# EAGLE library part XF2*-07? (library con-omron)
OMRON FPC Connector Source : http://www.omron.com/ecb/products/pdf/fpc.pdf

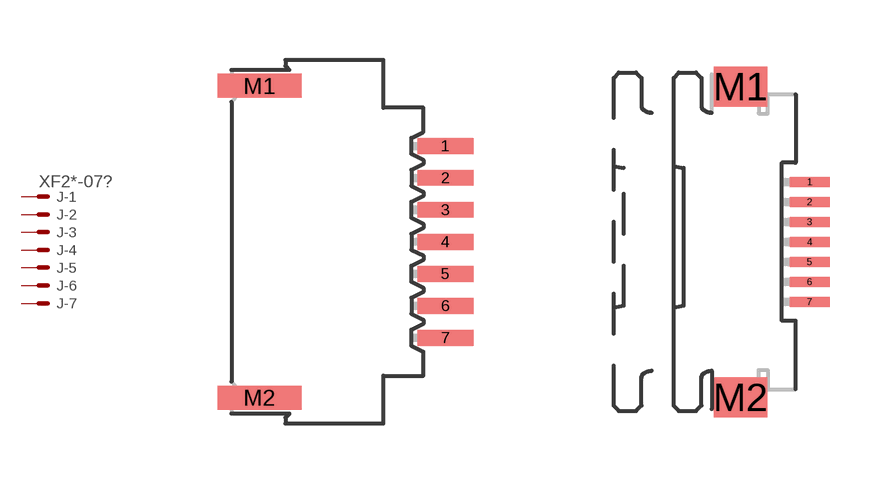
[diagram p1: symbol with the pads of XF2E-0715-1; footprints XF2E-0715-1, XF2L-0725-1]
Designator prefix J; gates -1=PV -2=P -3=P -4=P -5=P -6=P -7=P

## XF2E-0715-1 (OC_FARNELL: unknown; OC_NEWARK: unknown)  [XF2E-0715-1]
1  -1:MSV  pas
2  -2:MS  pas
3  -3:MS  pas
4  -4:MS  pas
5  -5:MS  pas
6  -6:MS  pas
7  -7:MS  pas

## XF2L-0725-1 (MPN: XF2L-0725-1; OC_FARNELL: unknown; OC_NEWARK: 37M0868)  [XF2L-0725-1]
Pads as for XF2E-0715-1

## XF2L-0735-1 (MPN: XF2L-0735-1; OC_FARNELL: unknown; OC_NEWARK: 37M0870)  [XF2L-0735-1]
Pads as for XF2E-0715-1

## Footprint XF2E-0715-1 (pad centres in mm)
Non-ZIF Type (0.8 mm-pitch) Source : http://www.omron.com/ecb/products/pdf/fpc.pdf
smd 1.4 x 0.4: 1 2.54,2.4; 2 2.54,1.6; 3 2.54,0.8; 4 2.54,0; 5 2.54,-0.8; 6 2.54,-1.6; 7 2.54,-2.4
smd 2.1 x 0.6: M1 -2.11,3.9; M2 -2.11,-3.9

## Footprint XF2L-0725-1 (pad centres in mm)
ZIF Slide-locking Type (0.5 mm-pitch) Upper-contact Type Source : http://www.omron.com/ecb/products/pdf/fpc.pdf
smd 1 x 0.25: 1 1.905,1.5; 2 1.905,1; 3 1.905,0.5; 4 1.905,0; 5 1.905,-0.5; 6 1.905,-1; 7 1.905,-1.5
smd 1.34 x 1: M1 0.18,3.888; M2 0.18,-3.888

## Footprint XF2L-0735-1 (pad centres in mm)
ZIF Slide-locking Type (0.5 mm-pitch) Lower-contact Type Source : http://www.omron.com/ecb/products/pdf/fpc.pdf
smd 1 x 0.25: 1 1.905,1.5; 2 1.905,1; 3 1.905,0.5; 4 1.905,0; 5 1.905,-0.5; 6 1.905,-1; 7 1.905,-1.5
smd 1.34 x 1: M1 0.18,3.888; M2 0.18,-3.888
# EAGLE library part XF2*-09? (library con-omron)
OMRON FPC Connector Source : http://www.omron.com/ecb/products/pdf/fpc.pdf

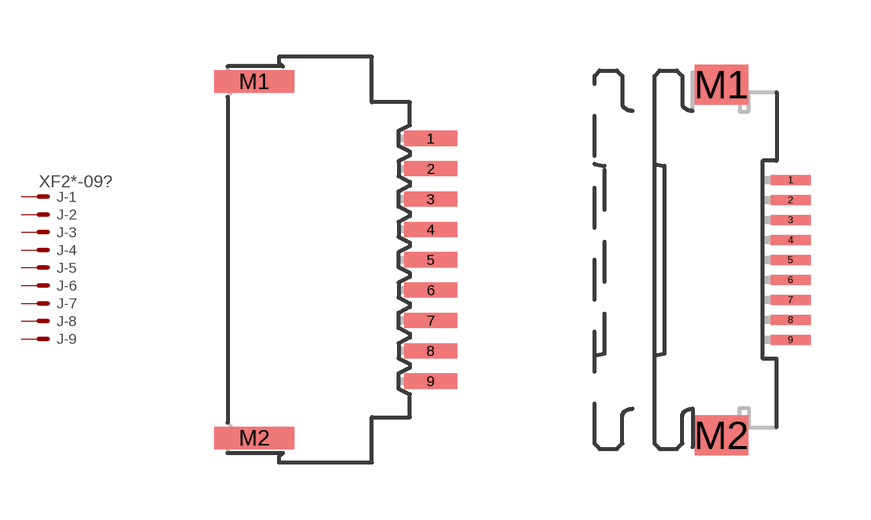
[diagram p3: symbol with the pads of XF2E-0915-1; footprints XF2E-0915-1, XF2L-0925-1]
Designator prefix J; gates -1=PV -2=P -3=P -4=P -5=P -6=P -7=P -8=P -9=P

## XF2E-0915-1 (MPN: XF2E-0915-1; OC_FARNELL: unknown; OC_NEWARK: 37M9452)  [XF2E-0915-1]
1  -1:MSV  pas
2  -2:MS  pas
3  -3:MS  pas
4  -4:MS  pas
5  -5:MS  pas
6  -6:MS  pas
7  -7:MS  pas
8  -8:MS  pas
9  -9:MS  pas

## XF2L-0925-1 (MPN: XF2L-0925-1A; OC_FARNELL: unknown; OC_NEWARK: 05M1991)  [XF2L-0925-1]
Pads as for XF2E-0915-1

## XF2R-0915-4A (MPN: XF2R-0915-4A; OC_FARNELL: unknown; OC_NEWARK: 37M0944)  [XF2R-0915-4A]
Pads as for XF2E-0915-1

## Footprint XF2E-0915-1 (pad centres in mm)
Non-ZIF Type (0.8 mm-pitch) Source : http://www.omron.com/ecb/products/pdf/fpc.pdf
smd 1.4 x 0.4: 1 2.54,3.2; 2 2.54,2.4; 3 2.54,1.6; 4 2.54,0.8; 5 2.54,0; 6 2.54,-0.8; 7 2.54,-1.6; 8 2.54,-2.4; 9 2.54,-3.2
smd 2.1 x 0.6: M1 -2.11,4.7; M2 -2.11,-4.7

## Footprint XF2L-0925-1 (pad centres in mm)
ZIF Slide-locking Type (0.5 mm-pitch) Upper-contact Type Source : http://www.omron.com/ecb/products/pdf/fpc.pdf
smd 1 x 0.25: 1 1.905,2; 2 1.905,1.5; 3 1.905,1; 4 1.905,0.5; 5 1.905,0; 6 1.905,-0.5; 7 1.905,-1; 8 1.905,-1.5; 9 1.905,-2
smd 1.34 x 1: M1 0.18,4.388; M2 0.18,-4.388

## Footprint XF2R-0915-4A (pad centres in mm)
Low-profile Rotary Backlock Type (0.5 mm-pitch) Source : http://www.omron.com/ecb/products/pdf/fpc.pdf
smd 0.85 x 0.25: 1 -2.54,2; 2 -2.54,1.5; 3 -2.54,1; 4 -2.54,0.5; 5 -2.54,0; 6 -2.54,-0.5; 7 -2.54,-1; 8 -2.54,-1.5; 9 -2.54,-2
smd 1.4 x 1: M1 -0.915,3.3; M2 -0.915,-3.3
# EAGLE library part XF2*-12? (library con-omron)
OMRON FPC Connector Source : http://www.omron.com/ecb/products/pdf/fpc.pdf

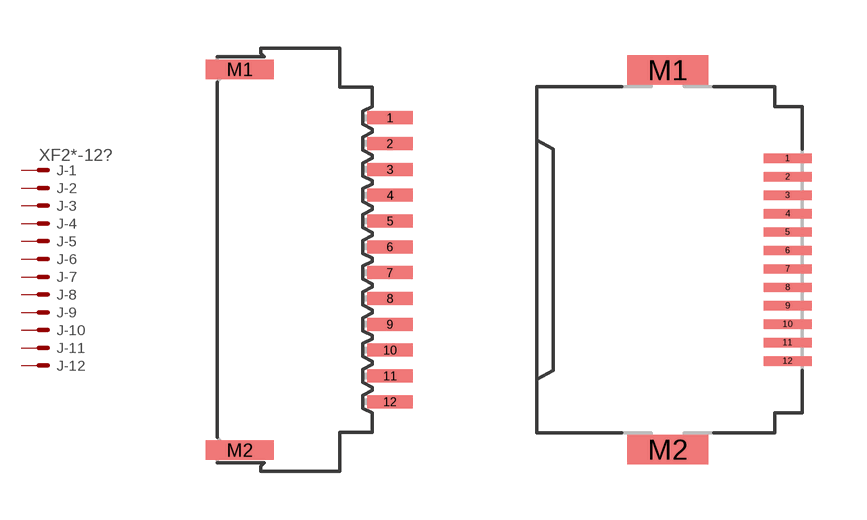
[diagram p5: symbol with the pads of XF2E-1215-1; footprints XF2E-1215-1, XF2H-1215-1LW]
Designator prefix J; gates -1=PV -2=P -3=P -4=P -5=P -6=P -7=P -8=P -9=P -10=P -11=P -12=P

## XF2E-1215-1 (OC_FARNELL: unknown; OC_NEWARK: unknown)  [XF2E-1215-1]
1  -1:MSV  pas
2  -2:MS  pas
3  -3:MS  pas
4  -4:MS  pas
5  -5:MS  pas
6  -6:MS  pas
7  -7:MS  pas
8  -8:MS  pas
9  -9:MS  pas
10  -10:MS  pas
11  -11:MS  pas
12  -12:MS  pas

## XF2H-1215-1LW (OC_FARNELL: unknown; OC_NEWARK: unknown)  [XF2H-1215-1LW]
Pads as for XF2E-1215-1

## XF2J-1224-11 (MPN: XF2J-1224-11A; OC_FARNELL: 1430936; OC_NEWARK: 37M0822)  [XF2J-1224-11]
Pads as for XF2E-1215-1

## XF2J-1224-12 (MPN: XF2J-1224-12A; OC_FARNELL: 1430940; OC_NEWARK: 59M3512)  [XF2J-1224-12]
Pads as for XF2E-1215-1

## XF2L-1225-1 (MPN: XF2L-1225-1A; OC_FARNELL: unknown; OC_NEWARK: 05M1993)  [XF2L-1225-1]
Pads as for XF2E-1215-1

## XF2L-1235-1 (MPN: XF2L-1235-1; OC_FARNELL: unknown; OC_NEWARK: 37M0880)  [XF2L-1235-1]
Pads as for XF2E-1215-1

## Footprint XF2E-1215-1 (pad centres in mm)
Non-ZIF Type (0.8 mm-pitch) Source : http://www.omron.com/ecb/products/pdf/fpc.pdf
smd 1.4 x 0.4: 1 2.54,4.4; 2 2.54,3.6; 3 2.54,2.8; 4 2.54,2; 5 2.54,1.2; 6 2.54,0.4; 7 2.54,-0.4; 8 2.54,-1.2; 9 2.54,-2; 10 2.54,-2.8; 11 2.54,-3.6; 12 2.54,-4.4
smd 2.1 x 0.6: M1 -2.11,5.9; M2 -2.11,-5.9

## Footprint XF2H-1215-1LW (pad centres in mm)
Standard Rotary Backlock Type (0.5 mm-pitch) Source : http://www.omron.com/ecb/products/pdf/fpc.pdf
smd 1.3 x 0.25: 1 3.175,2.75; 2 3.175,2.25; 3 3.175,1.75; 4 3.175,1.25; 5 3.175,0.75; 6 3.175,0.25; 7 3.175,-0.25; 8 3.175,-0.75; 9 3.175,-1.25; 10 3.175,-1.75; 11 3.175,-2.25; 12 3.175,-2.75
smd 2.2 x 0.8: M1 -0.075,5.15; M2 -0.075,-5.15

## Footprint XF2J-1224-11 (pad centres in mm)
ZIF Slide-locking Type (0.5 mm-pitch) Standard Source : http://www.omron.com/ecb/products/pdf/fpc.pdf
smd 1.6 x 0.5: 1 1.2,2.75; 2 -1.2,2.25; 3 1.2,1.75; 4 -1.2,1.25; 5 1.2,0.75; 6 -1.2,0.25; 7 1.2,-0.25; 8 -1.2,-0.75; 9 1.2,-1.25; 10 -1.2,-1.75; 11 1.2,-2.25; 12 -1.2,-2.75
smd 2.9 x 1.4: M1 0,4.45; M2 0,-4.45

## Footprint XF2J-1224-12 (pad centres in mm)
ZIF Slide-locking Type (0.5 mm-pitch) Reverse Source : http://www.omron.com/ecb/products/pdf/fpc.pdf
smd 1.6 x 0.5: 1 -1.2,2.75; 2 1.2,2.25; 3 -1.2,1.75; 4 1.2,1.25; 5 -1.2,0.75; 6 1.2,0.25; 7 -1.2,-0.25; 8 1.2,-0.75; 9 -1.2,-1.25; 10 1.2,-1.75; 11 -1.2,-2.25; 12 1.2,-2.75
smd 2.9 x 1.4: M1 0,4.45; M2 0,-4.45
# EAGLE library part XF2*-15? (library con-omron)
OMRON FPC Connector Source : http://www.omron.com/ecb/products/pdf/fpc.pdf

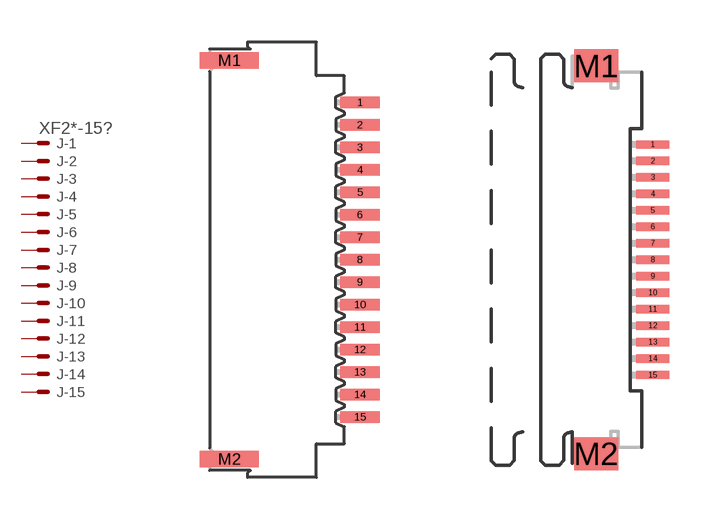
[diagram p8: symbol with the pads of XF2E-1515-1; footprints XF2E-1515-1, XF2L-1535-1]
Designator prefix J; gates -1=PV -2=P -3=P -4=P -5=P -6=P -7=P -8=P -9=P -10=P -11=P -12=P -13=P -14=P -15=P

## XF2E-1515-1 (OC_FARNELL: unknown; OC_NEWARK: unknown)  [XF2E-1515-1]
1  -1:MSV  pas
2  -2:MS  pas
3  -3:MS  pas
4  -4:MS  pas
5  -5:MS  pas
6  -6:MS  pas
7  -7:MS  pas
8  -8:MS  pas
9  -9:MS  pas
10  -10:MS  pas
11  -11:MS  pas
12  -12:MS  pas
13  -13:MS  pas
14  -14:MS  pas
15  -15:MS  pas

## XF2L-1535-1 (MPN: XF2L-1535-1A; OC_FARNELL: unknown; OC_NEWARK: 05M1997)  [XF2L-1535-1]
Pads as for XF2E-1515-1

## Footprint XF2E-1515-1 (pad centres in mm)
Non-ZIF Type (0.8 mm-pitch) Source : http://www.omron.com/ecb/products/pdf/fpc.pdf
smd 1.4 x 0.4: 1 2.54,5.6; 2 2.54,4.8; 3 2.54,4; 4 2.54,3.2; 5 2.54,2.4; 6 2.54,1.6; 7 2.54,0.8; 8 2.54,0; 9 2.54,-0.8; 10 2.54,-1.6; 11 2.54,-2.4; 12 2.54,-3.2; 13 2.54,-4; 14 2.54,-4.8; 15 2.54,-5.6
smd 2.1 x 0.6: M1 -2.11,7.1; M2 -2.11,-7.1

## Footprint XF2L-1535-1 (pad centres in mm)
ZIF Slide-locking Type (0.5 mm-pitch) Lower-contact Type Source : http://www.omron.com/ecb/products/pdf/fpc.pdf
smd 1 x 0.25: 1 1.905,3.5; 2 1.905,3; 3 1.905,2.5; 4 1.905,2; 5 1.905,1.5; 6 1.905,1; 7 1.905,0.5; 8 1.905,0; 9 1.905,-0.5; 10 1.905,-1; 11 1.905,-1.5; 12 1.905,-2; 13 1.905,-2.5; 14 1.905,-3; 15 1.905,-3.5
smd 1.34 x 1: M1 0.18,5.888; M2 0.18,-5.888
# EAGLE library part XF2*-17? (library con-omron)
OMRON FPC Connector Source : http://www.omron.com/ecb/products/pdf/fpc.pdf

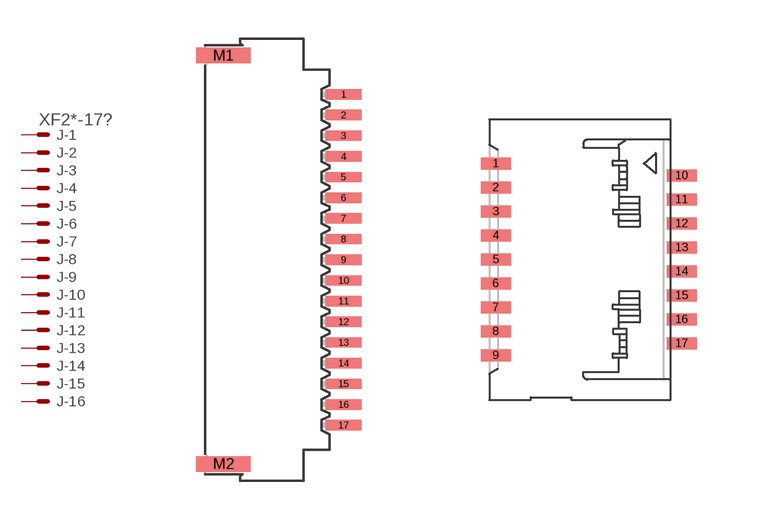
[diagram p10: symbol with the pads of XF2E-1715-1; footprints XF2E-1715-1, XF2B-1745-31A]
Designator prefix J; gates -1=PV -2=P -3=P -4=P -5=P -6=P -7=P -8=P -9=P -10=P -11=P -12=P -13=P -14=P -15=P -16=P -17=P

## XF2E-1717-1 (OC_FARNELL: unknown; OC_NEWARK: unknown)  [XF2E-1715-1]
1  -1:MSV  pas
2  -2:MS  pas
3  -3:MS  pas
4  -4:MS  pas
5  -5:MS  pas
6  -6:MS  pas
7  -7:MS  pas
8  -8:MS  pas
9  -9:MS  pas
10  -10:MS  pas
11  -11:MS  pas
12  -12:MS  pas
13  -13:MS  pas
14  -14:MS  pas
15  -15:MS  pas
16  -16:MS  pas
17  -17:MS  pas

## XF2B-1745-31A (MPN: XF2B-1745-31A; OC_FARNELL: unknown; OC_NEWARK: 37M0750)  [XF2B-1745-31A]
Pads as for XF2E-1715-1

## Footprint XF2E-1715-1 (pad centres in mm)
Non-ZIF Type (0.8 mm-pitch) Source : http://www.omron.com/ecb/products/pdf/fpc.pdf
smd 1.4 x 0.4: 1 2.54,6.4; 2 2.54,5.6; 3 2.54,4.8; 4 2.54,4; 5 2.54,3.2; 6 2.54,2.4; 7 2.54,1.6; 8 2.54,0.8; 9 2.54,0; 10 2.54,-0.8; 11 2.54,-1.6; 12 2.54,-2.4; 13 2.54,-3.2; 14 2.54,-4; 15 2.54,-4.8; 16 2.54,-5.6; 17 2.54,-6.4
smd 2.1 x 0.6: M1 -2.11,7.9; M2 -2.11,-7.9

## Footprint XF2B-1745-31A (pad centres in mm)
Rotary Backlock Type (0.3 mm-pitch) Source : http://www.omron.com/ecb/products/pdf/fpc.pdf
smd 0.75 x 0.3: 1 -2.325,2.4; 2 -2.325,1.8; 3 -2.325,1.2; 4 -2.325,0.6; 5 -2.325,0; 6 -2.325,-0.6; 7 -2.325,-1.2; 8 -2.325,-1.8; 9 -2.325,-2.4; 10 2.325,2.1; 11 2.325,1.5; 12 2.325,0.9; 13 2.325,0.3; 14 2.325,-0.3; 15 2.325,-0.9; 16 2.325,-1.5; 17 2.325,-2.1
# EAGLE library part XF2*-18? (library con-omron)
OMRON FPC Connector Source : http://www.omron.com/ecb/products/pdf/fpc.pdf

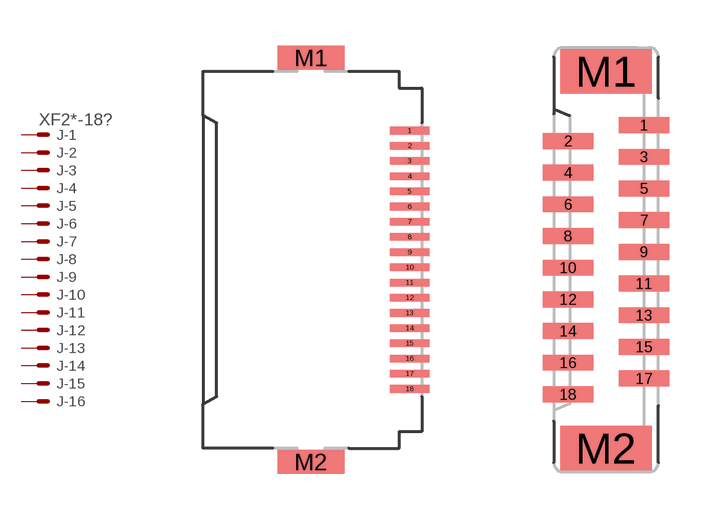
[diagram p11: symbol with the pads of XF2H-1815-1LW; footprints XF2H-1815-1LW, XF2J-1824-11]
Designator prefix J; gates -1=PV -2=P -3=P -4=P -5=P -6=P -7=P -8=P -9=P -10=P -11=P -12=P -13=P -14=P -15=P -16=P -17=P -18=P

## XF2H-1815-1LW (MF: OMRON COMPONENTS USA; MPN: XF2H-1815-1LW; OC_FARNELL: unknown; OC_NEWARK: 12J5138)  [XF2H-1815-1LW]
1  -1:MSV  pas
2  -2:MS  pas
3  -3:MS  pas
4  -4:MS  pas
5  -5:MS  pas
6  -6:MS  pas
7  -7:MS  pas
8  -8:MS  pas
9  -9:MS  pas
10  -10:MS  pas
11  -11:MS  pas
12  -12:MS  pas
13  -13:MS  pas
14  -14:MS  pas
15  -15:MS  pas
16  -16:MS  pas
17  -17:MS  pas
18  -18:MS  pas

## XF2J-1824-11 (MF: OMRON COMPONENTS USA; MPN: XF2J-1824-11; OC_FARNELL: unknown; OC_NEWARK: 89C8565)  [XF2J-1824-11]
Pads as for XF2H-1815-1LW

## XF2J-1824-12 (OC_FARNELL: unknown; OC_NEWARK: unknown)  [XF2J-1824-12]
Pads as for XF2H-1815-1LW

## XF2L-1825-1 (MPN: XF2L-1825-1A; OC_FARNELL: unknown; OC_NEWARK: 05M1999)  [XF2L-1825-1]
Pads as for XF2H-1815-1LW

## XF2L-1835-1 (MF: OMRON COMPONENTS USA; MPN: XF2L-1835-1; OC_FARNELL: 1430929; OC_NEWARK: 89C8591)  [XF2L-1835-1]
Pads as for XF2H-1815-1LW

## XF2R-1815-4A (MPN: XF2R-1815-4A; OC_FARNELL: unknown; OC_NEWARK: 37M0945)  [XF2R-1815-4A]
Pads as for XF2H-1815-1LW

## Footprint XF2H-1815-1LW (pad centres in mm)
Standard Rotary Backlock Type (0.5 mm-pitch) Source: fpc.pdf
smd 1.3 x 0.25: 1 3.175,4.25; 2 3.175,3.75; 3 3.175,3.25; 4 3.175,2.75; 5 3.175,2.25; 6 3.175,1.75; 7 3.175,1.25; 8 3.175,0.75; 9 3.175,0.25; 10 3.175,-0.25; 11 3.175,-0.75; 12 3.175,-1.25; 13 3.175,-1.75; 14 3.175,-2.25; 15 3.175,-2.75; 16 3.175,-3.25; 17 3.175,-3.75; 18 3.175,-4.25
smd 2.2 x 0.8: M1 -0.075,6.65; M2 -0.075,-6.65

## Footprint XF2J-1824-11 (pad centres in mm)
ZIF Slide-locking Type (0.5 mm-pitch) Standard Source : http://www.omron.com/ecb/products/pdf/fpc.pdf
smd 1.6 x 0.5: 1 1.2,4.25; 2 -1.2,3.75; 3 1.2,3.25; 4 -1.2,2.75; 5 1.2,2.25; 6 -1.2,1.75; 7 1.2,1.25; 8 -1.2,0.75; 9 1.2,0.25; 10 -1.2,-0.25; 11 1.2,-0.75; 12 -1.2,-1.25; 13 1.2,-1.75; 14 -1.2,-2.25; 15 1.2,-2.75; 16 -1.2,-3.25; 17 1.2,-3.75; 18 -1.2,-4.25
smd 2.9 x 1.4: M1 0,5.95; M2 0,-5.95

## Footprint XF2J-1824-12 (pad centres in mm)
ZIF Slide-locking Type (0.5 mm-pitch) Reverse Source : http://www.omron.com/ecb/products/pdf/fpc.pdf
smd 1.6 x 0.5: 1 -1.2,4.25; 2 1.2,3.75; 3 -1.2,3.25; 4 1.2,2.75; 5 -1.2,2.25; 6 1.2,1.75; 7 -1.2,1.25; 8 1.2,0.75; 9 -1.2,0.25; 10 1.2,-0.25; 11 -1.2,-0.75; 12 1.2,-1.25; 13 -1.2,-1.75; 14 1.2,-2.25; 15 -1.2,-2.75; 16 1.2,-3.25; 17 -1.2,-3.75; 18 1.2,-4.25
smd 2.9 x 1.4: M1 0,5.95; M2 0,-5.95

## Footprint XF2L-1825-1 (pad centres in mm)
ZIF Slide-locking Type (0.5 mm-pitch) Upper-contact Type Source : http://www.omron.com/ecb/products/pdf/fpc.pdf
smd 1 x 0.25: 1 1.905,4.25; 2 1.905,3.75; 3 1.905,3.25; 4 1.905,2.75; 5 1.905,2.25; 6 1.905,1.75; 7 1.905,1.25; 8 1.905,0.75; 9 1.905,0.25; 10 1.905,-0.25; 11 1.905,-0.75; 12 1.905,-1.25; 13 1.905,-1.75; 14 1.905,-2.25; 15 1.905,-2.75; 16 1.905,-3.25; 17 1.905,-3.75; 18 1.905,-4.25
smd 1.34 x 1: M1 0.18,6.638; M2 0.18,-6.638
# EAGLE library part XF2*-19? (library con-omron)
OMRON FPC Connector Source : http://www.omron.com/ecb/products/pdf/fpc.pdf

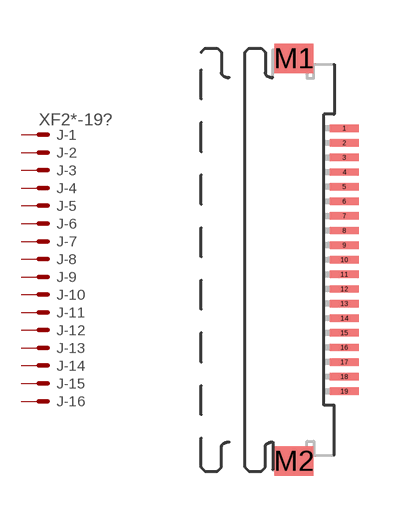
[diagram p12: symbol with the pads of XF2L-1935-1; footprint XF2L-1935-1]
Designator prefix J; gates -1=PV -2=P -3=P -4=P -5=P -6=P -7=P -8=P -9=P -10=P -11=P -12=P -13=P -14=P -15=P -16=P -17=P -18=P -19=P

## XF2L-1935-1 (MPN: XF2L-1935-1A; OC_FARNELL: unknown; OC_NEWARK: 05M2001)  [XF2L-1935-1]
1  -1:MSV  pas
2  -2:MS  pas
3  -3:MS  pas
4  -4:MS  pas
5  -5:MS  pas
6  -6:MS  pas
7  -7:MS  pas
8  -8:MS  pas
9  -9:MS  pas
10  -10:MS  pas
11  -11:MS  pas
12  -12:MS  pas
13  -13:MS  pas
14  -14:MS  pas
15  -15:MS  pas
16  -16:MS  pas
17  -17:MS  pas
18  -18:MS  pas
19  -19:MS  pas

## Footprint XF2L-1935-1 (pad centres in mm)
ZIF Slide-locking Type (0.5 mm-pitch) Lower-contact Type Source : http://www.omron.com/ecb/products/pdf/fpc.pdf
smd 1 x 0.25: 1 1.905,4.5; 2 1.905,4; 3 1.905,3.5; 4 1.905,3; 5 1.905,2.5; 6 1.905,2; 7 1.905,1.5; 8 1.905,1; 9 1.905,0.5; 10 1.905,0; 11 1.905,-0.5; 12 1.905,-1; 13 1.905,-1.5; 14 1.905,-2; 15 1.905,-2.5; 16 1.905,-3; 17 1.905,-3.5; 18 1.905,-4; 19 1.905,-4.5
smd 1.34 x 1: M1 0.18,6.888; M2 0.18,-6.888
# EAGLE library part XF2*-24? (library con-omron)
OMRON FPC Connector Source : http://www.omron.com/ecb/products/pdf/fpc.pdf

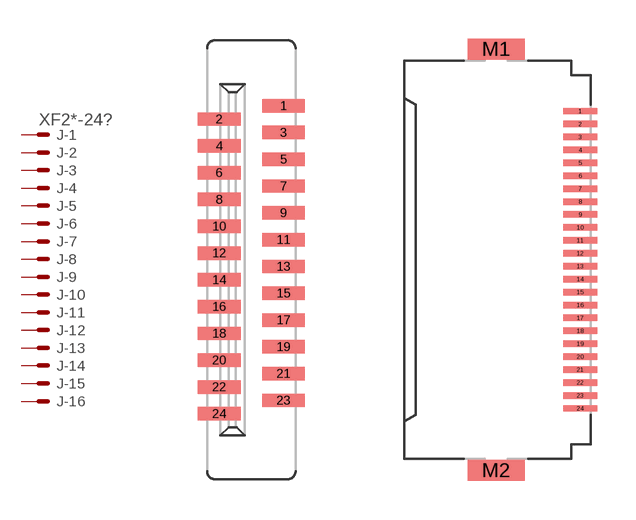
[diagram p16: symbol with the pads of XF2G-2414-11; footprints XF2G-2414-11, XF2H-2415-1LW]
Designator prefix J; gates -1=PV -2=P -3=P -4=P -5=P -6=P -7=P -8=P -9=P -10=P -11=P -12=P -13=P -14=P -15=P -16=P -17=P -18=P -19=P -20=P -21=P -22=P -23=P -24=P

## XF2G-2414-11 (OC_FARNELL: unknown; OC_NEWARK: unknown)  [XF2G-2414-11]
1  -1:MSV  pas
2  -2:MS  pas
3  -3:MS  pas
4  -4:MS  pas
5  -5:MS  pas
6  -6:MS  pas
7  -7:MS  pas
8  -8:MS  pas
9  -9:MS  pas
10  -10:MS  pas
11  -11:MS  pas
12  -12:MS  pas
13  -13:MS  pas
14  -14:MS  pas
15  -15:MS  pas
16  -16:MS  pas
17  -17:MS  pas
18  -18:MS  pas
19  -19:MS  pas
20  -20:MS  pas
21  -21:MS  pas
22  -22:MS  pas
23  -23:MS  pas
24  -24:MS  pas

## XF2H-2415-1LW (MF: OMRON COMPONENTS USA; MPN: XF2H-2415-1LW; OC_FARNELL: unknown; OC_NEWARK: 12J5142)  [XF2H-2415-1LW]
Pads as for XF2G-2414-11

## XF2J-2424-11 (MF: OMRON COMPONENTS USA; MPN: XF2J-2424-11A; OC_FARNELL: 1206270; OC_NEWARK: 87K0738)  [XF2J-2424-11]
Pads as for XF2G-2414-11

## XF2L-2435-1 (MPN: XF2L-2435-1A; OC_FARNELL: unknown; OC_NEWARK: 05M2005)  [XF2L-2435-1]
Pads as for XF2G-2414-11

## XF2J-2424-12 (OC_FARNELL: unknown; OC_NEWARK: unknown)  [XF2J-2424-12]
Pads as for XF2G-2414-11

## XF2R-2415-4A (MPN: XF2R-2415-4A; OC_FARNELL: unknown; OC_NEWARK: 37M0946)  [XF2R-2415-4A]
Pads as for XF2G-2414-11

## Footprint XF2G-2414-11 (pad centres in mm)
Non-ZIF Type (0.5 mm-pitch) Source : http://www.omron.com/ecb/products/pdf/fpc.pdf
smd 1.6 x 0.5: 1 1.2,5.75; 2 -1.2,5.25; 3 1.2,4.75; 4 -1.2,4.25; 5 1.2,3.75; 6 -1.2,3.25; 7 1.2,2.75; 8 -1.2,2.25; 9 1.2,1.75; 10 -1.2,1.25; 11 1.2,0.75; 12 -1.2,0.25; 13 1.2,-0.25; 14 -1.2,-0.75; 15 1.2,-1.25; 16 -1.2,-1.75; 17 1.2,-2.25; 18 -1.2,-2.75; 19 1.2,-3.25; 20 -1.2,-3.75; 21 1.2,-4.25; 22 -1.2,-4.75; 23 1.2,-5.25; 24 -1.2,-5.75

## Footprint XF2H-2415-1LW (pad centres in mm)
Standard Rotary Backlock Type (0.5 mm-pitch) Source : http://www.omron.com/ecb/products/pdf/fpc.pdf
smd 1.3 x 0.25: 1 3.175,5.75; 2 3.175,5.25; 3 3.175,4.75; 4 3.175,4.25; 5 3.175,3.75; 6 3.175,3.25; 7 3.175,2.75; 8 3.175,2.25; 9 3.175,1.75; 10 3.175,1.25; 11 3.175,0.75; 12 3.175,0.25; 13 3.175,-0.25; 14 3.175,-0.75; 15 3.175,-1.25; 16 3.175,-1.75; 17 3.175,-2.25; 18 3.175,-2.75; 19 3.175,-3.25; 20 3.175,-3.75; 21 3.175,-4.25; 22 3.175,-4.75; 23 3.175,-5.25; 24 3.175,-5.75
smd 2.2 x 0.8: M1 -0.075,8.15; M2 -0.075,-8.15

## Footprint XF2J-2424-11 (pad centres in mm)
ZIF Slide-locking Type (0.5 mm-pitch) Standard Source : http://www.omron.com/ecb/products/pdf/fpc.pdf
smd 1.6 x 0.5: 1 1.2,5.75; 2 -1.2,5.25; 3 1.2,4.75; 4 -1.2,4.25; 5 1.2,3.75; 6 -1.2,3.25; 7 1.2,2.75; 8 -1.2,2.25; 9 1.2,1.75; 10 -1.2,1.25; 11 1.2,0.75; 12 -1.2,0.25; 13 1.2,-0.25; 14 -1.2,-0.75; 15 1.2,-1.25; 16 -1.2,-1.75; 17 1.2,-2.25; 18 -1.2,-2.75; 19 1.2,-3.25; 20 -1.2,-3.75; 21 1.2,-4.25; 22 -1.2,-4.75; 23 1.2,-5.25; 24 -1.2,-5.75
smd 2.9 x 1.4: M1 0,7.45; M2 0,-7.45

## Footprint XF2L-2435-1 (pad centres in mm)
ZIF Slide-locking Type (0.5 mm-pitch) Lower-contact Type Source : http://www.omron.com/ecb/products/pdf/fpc.pdf
smd 1 x 0.25: 1 1.905,5.75; 2 1.905,5.25; 3 1.905,4.75; 4 1.905,4.25; 5 1.905,3.75; 6 1.905,3.25; 7 1.905,2.75; 8 1.905,2.25; 9 1.905,1.75; 10 1.905,1.25; 11 1.905,0.75; 12 1.905,0.25; 13 1.905,-0.25; 14 1.905,-0.75; 15 1.905,-1.25; 16 1.905,-1.75; 17 1.905,-2.25; 18 1.905,-2.75; 19 1.905,-3.25; 20 1.905,-3.75; 21 1.905,-4.25; 22 1.905,-4.75; 23 1.905,-5.25; 24 1.905,-5.75
smd 1.34 x 1: M1 0.18,8.137; M2 0.18,-8.137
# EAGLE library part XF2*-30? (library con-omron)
OMRON FPC Connector Source : http://www.omron.com/ecb/products/pdf/fpc.pdf

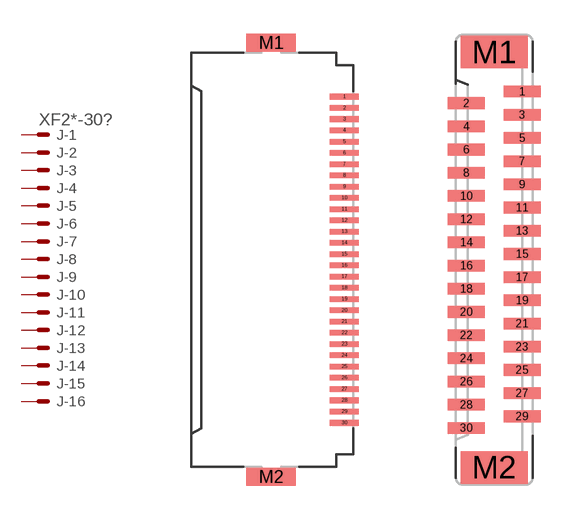
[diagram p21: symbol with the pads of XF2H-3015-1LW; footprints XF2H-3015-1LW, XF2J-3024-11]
Designator prefix J; gates -1=PV -2=P -3=P -4=P -5=P -6=P -7=P -8=P -9=P -10=P -11=P -12=P -13=P -14=P -15=P -16=P -17=P -18=P -19=P -20=P -21=P -22=P -23=P -24=P -25=P -26=P -27=P -28=P -29=P -30=P

## XF2-3015-1LW (OC_FARNELL: unknown; OC_NEWARK: unknown)  [XF2H-3015-1LW]
1  -1:MSV  pas
2  -2:MS  pas
3  -3:MS  pas
4  -4:MS  pas
5  -5:MS  pas
6  -6:MS  pas
7  -7:MS  pas
8  -8:MS  pas
9  -9:MS  pas
10  -10:MS  pas
11  -11:MS  pas
12  -12:MS  pas
13  -13:MS  pas
14  -14:MS  pas
15  -15:MS  pas
16  -16:MS  pas
17  -17:MS  pas
18  -18:MS  pas
19  -19:MS  pas
20  -20:MS  pas
21  -21:MS  pas
22  -22:MS  pas
23  -23:MS  pas
24  -24:MS  pas
25  -25:MS  pas
26  -26:MS  pas
27  -27:MS  pas
28  -28:MS  pas
29  -29:MS  pas
30  -30:MS  pas

## XF2J-3024-11 (MPN: XF2J-3024-11; OC_FARNELL: 1430938; OC_NEWARK: 37M0856)  [XF2J-3024-11]
Pads as for XF2H-3015-1LW

## XF2L-3025-1 (MPN: XF2L-3025-1A; OC_FARNELL: 1536111; OC_NEWARK: 05M2007)  [XF2L-3025-1]
Pads as for XF2H-3015-1LW

## XF2L-3035-1 (MPN: XF2L-3035-1A; OC_FARNELL: 1430931; OC_NEWARK: 05M2008)  [XF2L-3035-1]
Pads as for XF2H-3015-1LW

## Footprint XF2H-3015-1LW (pad centres in mm)
Standard Rotary Backlock Type (0.5 mm-pitch) Source : http://www.omron.com/ecb/products/pdf/fpc.pdf
smd 1.3 x 0.25: 1 3.175,7.25; 2 3.175,6.75; 3 3.175,6.25; 4 3.175,5.75; 5 3.175,5.25; 6 3.175,4.75; 7 3.175,4.25; 8 3.175,3.75; 9 3.175,3.25; 10 3.175,2.75; 11 3.175,2.25; 12 3.175,1.75; 13 3.175,1.25; 14 3.175,0.75; 15 3.175,0.25; 16 3.175,-0.25; 17 3.175,-0.75; 18 3.175,-1.25; 19 3.175,-1.75; 20 3.175,-2.25; 21 3.175,-2.75; 22 3.175,-3.25; 23 3.175,-3.75; 24 3.175,-4.25; 25 3.175,-4.75; 26 3.175,-5.25; 27 3.175,-5.75; 28 3.175,-6.25; 29 3.175,-6.75; 30 3.175,-7.25
smd 2.2 x 0.8: M1 -0.075,9.65; M2 -0.075,-9.65

## Footprint XF2J-3024-11 (pad centres in mm)
ZIF Slide-locking Type (0.5 mm-pitch) Standard Source : http://www.omron.com/ecb/products/pdf/fpc.pdf
smd 1.6 x 0.5: 1 1.2,7.25; 2 -1.2,6.75; 3 1.2,6.25; 4 -1.2,5.75; 5 1.2,5.25; 6 -1.2,4.75; 7 1.2,4.25; 8 -1.2,3.75; 9 1.2,3.25; 10 -1.2,2.75; 11 1.2,2.25; 12 -1.2,1.75; 13 1.2,1.25; 14 -1.2,0.75; 15 1.2,0.25; 16 -1.2,-0.25; 17 1.2,-0.75; 18 -1.2,-1.25; 19 1.2,-1.75; 20 -1.2,-2.25; 21 1.2,-2.75; 22 -1.2,-3.25; 23 1.2,-3.75; 24 -1.2,-4.25; 25 1.2,-4.75; 26 -1.2,-5.25; 27 1.2,-5.75; 28 -1.2,-6.25; 29 1.2,-6.75; 30 -1.2,-7.25
smd 2.9 x 1.4: M1 0,8.95; M2 0,-8.95

## Footprint XF2L-3025-1 (pad centres in mm)
ZIF Slide-locking Type (0.5 mm-pitch) Upper-contact Type Source : http://www.omron.com/ecb/products/pdf/fpc.pdf
smd 1 x 0.25: 1 1.905,7.25; 2 1.905,6.75; 3 1.905,6.25; 4 1.905,5.75; 5 1.905,5.25; 6 1.905,4.75; 7 1.905,4.25; 8 1.905,3.75; 9 1.905,3.25; 10 1.905,2.75; 11 1.905,2.25; 12 1.905,1.75; 13 1.905,1.25; 14 1.905,0.75; 15 1.905,0.25; 16 1.905,-0.25; 17 1.905,-0.75; 18 1.905,-1.25; 19 1.905,-1.75; 20 1.905,-2.25; 21 1.905,-2.75; 22 1.905,-3.25; 23 1.905,-3.75; 24 1.905,-4.25; 25 1.905,-4.75; 26 1.905,-5.25; 27 1.905,-5.75; 28 1.905,-6.25; 29 1.905,-6.75; 30 1.905,-7.25
smd 1.34 x 1: M1 0.18,9.637; M2 0.18,-9.637

## Footprint XF2L-3035-1 (pad centres in mm)
ZIF Slide-locking Type (0.5 mm-pitch) Lower-contact Type Source : http://www.omron.com/ecb/products/pdf/fpc.pdf
smd 1 x 0.25: 1 1.905,7.25; 2 1.905,6.75; 3 1.905,6.25; 4 1.905,5.75; 5 1.905,5.25; 6 1.905,4.75; 7 1.905,4.25; 8 1.905,3.75; 9 1.905,3.25; 10 1.905,2.75; 11 1.905,2.25; 12 1.905,1.75; 13 1.905,1.25; 14 1.905,0.75; 15 1.905,0.25; 16 1.905,-0.25; 17 1.905,-0.75; 18 1.905,-1.25; 19 1.905,-1.75; 20 1.905,-2.25; 21 1.905,-2.75; 22 1.905,-3.25; 23 1.905,-3.75; 24 1.905,-4.25; 25 1.905,-4.75; 26 1.905,-5.25; 27 1.905,-5.75; 28 1.905,-6.25; 29 1.905,-6.75; 30 1.905,-7.25
smd 1.34 x 1: M1 0.18,9.637; M2 0.18,-9.637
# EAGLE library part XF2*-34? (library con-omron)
OMRON FPC Connector Source : http://www.omron.com/ecb/products/pdf/fpc.pdf

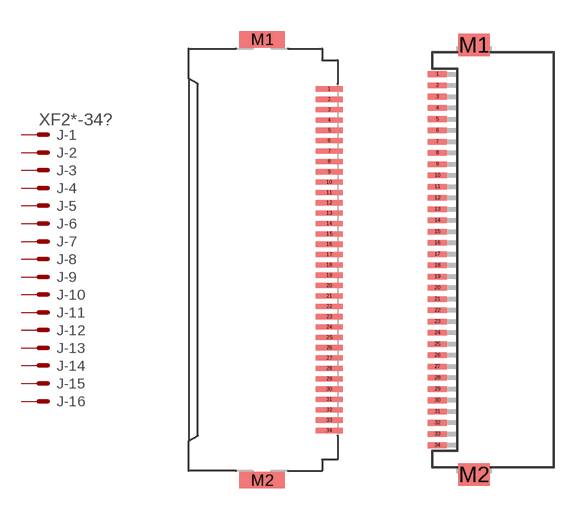
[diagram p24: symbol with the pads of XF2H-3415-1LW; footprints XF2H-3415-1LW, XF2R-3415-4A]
Designator prefix J; gates -1=PV -2=P -3=P -4=P -5=P -6=P -7=P -8=P -9=P -10=P -11=P -12=P -13=P -14=P -15=P -16=P -17=P -18=P -19=P -20=P -21=P -22=P -23=P -24=P -25=P -26=P -27=P -28=P -29=P -30=P -31=P -32=P -33=P -34=P

## XF2H-3415-1LW (MF: OMRON COMPONENTS USA; MPN: XF2H-3415-1LW; OC_FARNELL: unknown; OC_NEWARK: 12J5147)  [XF2H-3415-1LW]
1  -1:MSV  pas
2  -2:MS  pas
3  -3:MS  pas
4  -4:MS  pas
5  -5:MS  pas
6  -6:MS  pas
7  -7:MS  pas
8  -8:MS  pas
9  -9:MS  pas
10  -10:MS  pas
11  -11:MS  pas
12  -12:MS  pas
13  -13:MS  pas
14  -14:MS  pas
15  -15:MS  pas
16  -16:MS  pas
17  -17:MS  pas
18  -18:MS  pas
19  -19:MS  pas
20  -20:MS  pas
21  -21:MS  pas
22  -22:MS  pas
23  -23:MS  pas
24  -24:MS  pas
25  -25:MS  pas
26  -26:MS  pas
27  -27:MS  pas
28  -28:MS  pas
29  -29:MS  pas
30  -30:MS  pas
31  -31:MS  pas
32  -32:MS  pas
33  -33:MS  pas
34  -34:MS  pas

## XF2R-3415-4A (MPN: XF2R-3415-4A; OC_FARNELL: unknown; OC_NEWARK: 37M0947)  [XF2R-3415-4A]
Pads as for XF2H-3415-1LW

## Footprint XF2H-3415-1LW (pad centres in mm)
Standard Rotary Backlock Type (0.5 mm-pitch) Source : http://www.omron.com/ecb/products/pdf/fpc.pdf
smd 1.3 x 0.25: 1 3.175,8.25; 2 3.175,7.75; 3 3.175,7.25; 4 3.175,6.75; 5 3.175,6.25; 6 3.175,5.75; 7 3.175,5.25; 8 3.175,4.75; 9 3.175,4.25; 10 3.175,3.75; 11 3.175,3.25; 12 3.175,2.75; 13 3.175,2.25; 14 3.175,1.75; 15 3.175,1.25; 16 3.175,0.75; 17 3.175,0.25; 18 3.175,-0.25; 19 3.175,-0.75; 20 3.175,-1.25; 21 3.175,-1.75; 22 3.175,-2.25; 23 3.175,-2.75; 24 3.175,-3.25; 25 3.175,-3.75; 26 3.175,-4.25; 27 3.175,-4.75; 28 3.175,-5.25; 29 3.175,-5.75; 30 3.175,-6.25; 31 3.175,-6.75; 32 3.175,-7.25; 33 3.175,-7.75; 34 3.175,-8.25
smd 2.2 x 0.8: M1 -0.075,10.65; M2 -0.075,-10.65

## Footprint XF2R-3415-4A (pad centres in mm)
Low-profile Rotary Backlock Type (0.5 mm-pitch) Source : http://www.omron.com/ecb/products/pdf/fpc.pdf
smd 0.85 x 0.25: 1 -2.54,8.25; 2 -2.54,7.75; 3 -2.54,7.25; 4 -2.54,6.75; 5 -2.54,6.25; 6 -2.54,5.75; 7 -2.54,5.25; 8 -2.54,4.75; 9 -2.54,4.25; 10 -2.54,3.75; 11 -2.54,3.25; 12 -2.54,2.75; 13 -2.54,2.25; 14 -2.54,1.75; 15 -2.54,1.25; 16 -2.54,0.75; 17 -2.54,0.25; 18 -2.54,-0.25; 19 -2.54,-0.75; 20 -2.54,-1.25; 21 -2.54,-1.75; 22 -2.54,-2.25; 23 -2.54,-2.75; 24 -2.54,-3.25; 25 -2.54,-3.75; 26 -2.54,-4.25; 27 -2.54,-4.75; 28 -2.54,-5.25; 29 -2.54,-5.75; 30 -2.54,-6.25; 31 -2.54,-6.75; 32 -2.54,-7.25; 33 -2.54,-7.75; 34 -2.54,-8.25
smd 1.4 x 1: M1 -0.915,9.55; M2 -0.915,-9.55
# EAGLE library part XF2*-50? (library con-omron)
OMRON FPC Connector Source : http://www.omron.com/ecb/products/pdf/fpc.pdf

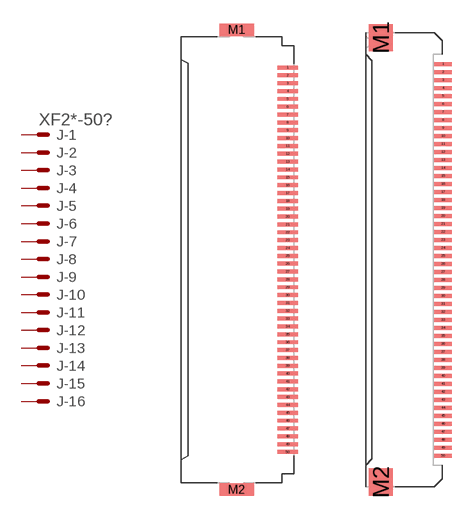
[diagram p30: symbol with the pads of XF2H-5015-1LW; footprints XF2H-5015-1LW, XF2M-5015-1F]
Designator prefix J; gates -1=PV -2=P -3=P -4=P -5=P -6=P -7=P -8=P -9=P -10=P -11=P -12=P -13=P -14=P -15=P -16=P -17=P -18=P -19=P -20=P -21=P -22=P -23=P -24=P -25=P -26=P -27=P -28=P -29=P -30=P -31=P -32=P -33=P -34=P -35=P -36=P -37=P -38=P -39=P -40=P -41=P -42=P -43=P -44=P -45=P -46=P -47=P -48=P -49=P -50=P

## XF2H-5015-1LW (OC_FARNELL: unknown; OC_NEWARK: unknown)  [XF2H-5015-1LW]
1  -1:MSV  pas
2  -2:MS  pas
3  -3:MS  pas
4  -4:MS  pas
5  -5:MS  pas
6  -6:MS  pas
7  -7:MS  pas
8  -8:MS  pas
9  -9:MS  pas
10  -10:MS  pas
11  -11:MS  pas
12  -12:MS  pas
13  -13:MS  pas
14  -14:MS  pas
15  -15:MS  pas
16  -16:MS  pas
17  -17:MS  pas
18  -18:MS  pas
19  -19:MS  pas
20  -20:MS  pas
21  -21:MS  pas
22  -22:MS  pas
23  -23:MS  pas
24  -24:MS  pas
25  -25:MS  pas
26  -26:MS  pas
27  -27:MS  pas
28  -28:MS  pas
29  -29:MS  pas
30  -30:MS  pas
31  -31:MS  pas
32  -32:MS  pas
33  -33:MS  pas
34  -34:MS  pas
35  -35:MS  pas
36  -36:MS  pas
37  -37:MS  pas
38  -38:MS  pas
39  -39:MS  pas
40  -40:MS  pas
41  -41:MS  pas
42  -42:MS  pas
43  -43:MS  pas
44  -44:MS  pas
45  -45:MS  pas
46  -46:MS  pas
47  -47:MS  pas
48  -48:MS  pas
49  -49:MS  pas
50  -50:MS  pas

## XF2M-5015-1F (OC_FARNELL: unknown; OC_NEWARK: unknown)  [XF2M-5015-1F]
Pads as for XF2H-5015-1LW

## Footprint XF2H-5015-1LW (pad centres in mm)
Standard Rotary Backlock Type (0.5 mm-pitch) Source : http://www.omron.com/ecb/products/pdf/fpc.pdf
smd 1.3 x 0.25: 1 3.175,12.25; 2 3.175,11.75; 3 3.175,11.25; 4 3.175,10.75; 5 3.175,10.25; 6 3.175,9.75; 7 3.175,9.25; 8 3.175,8.75; 9 3.175,8.25; 10 3.175,7.75; 11 3.175,7.25; 12 3.175,6.75; 13 3.175,6.25; 14 3.175,5.75; 15 3.175,5.25; 16 3.175,4.75; 17 3.175,4.25; 18 3.175,3.75; 19 3.175,3.25; 20 3.175,2.75; 21 3.175,2.25; 22 3.175,1.75; 23 3.175,1.25; 24 3.175,0.75; 25 3.175,0.25; 26 3.175,-0.25; 27 3.175,-0.75; 28 3.175,-1.25; 29 3.175,-1.75; 30 3.175,-2.25; 31 3.175,-2.75; 32 3.175,-3.25; 33 3.175,-3.75; 34 3.175,-4.25; 35 3.175,-4.75; 36 3.175,-5.25; 37 3.175,-5.75; 38 3.175,-6.25; 39 3.175,-6.75; 40 3.175,-7.25; 41 3.175,-7.75; 42 3.175,-8.25; 43 3.175,-8.75; 44 3.175,-9.25; 45 3.175,-9.75; 46 3.175,-10.25; 47 3.175,-10.75; 48 3.175,-11.25; 49 3.175,-11.75; 50 3.175,-12.25
smd 2.2 x 0.8: M1 -0.075,14.65; M2 -0.075,-14.65

## Footprint XF2M-5015-1F (pad centres in mm)
Reduced-area Rotary Backlock Type (0.5 mm-pitch) Source : http://www.omron.com/ecb/products/pdf/fpc.pdf
smd 1.1 x 0.25: 1 2.54,12.25; 2 2.54,11.75; 3 2.54,11.25; 4 2.54,10.75; 5 2.54,10.25; 6 2.54,9.75; 7 2.54,9.25; 8 2.54,8.75; 9 2.54,8.25; 10 2.54,7.75; 11 2.54,7.25; 12 2.54,6.75; 13 2.54,6.25; 14 2.54,5.75; 15 2.54,5.25; 16 2.54,4.75; 17 2.54,4.25; 18 2.54,3.75; 19 2.54,3.25; 20 2.54,2.75; 21 2.54,2.25; 22 2.54,1.75; 23 2.54,1.25; 24 2.54,0.75; 25 2.54,0.25; 26 2.54,-0.25; 27 2.54,-0.75; 28 2.54,-1.25; 29 2.54,-1.75; 30 2.54,-2.25; 31 2.54,-2.75; 32 2.54,-3.25; 33 2.54,-3.75; 34 2.54,-4.25; 35 2.54,-4.75; 36 2.54,-5.25; 37 2.54,-5.75; 38 2.54,-6.25; 39 2.54,-6.75; 40 2.54,-7.25; 41 2.54,-7.75; 42 2.54,-8.25; 43 2.54,-8.75; 44 2.54,-9.25; 45 2.54,-9.75; 46 2.54,-10.25; 47 2.54,-10.75; 48 2.54,-11.25; 49 2.54,-11.75; 50 2.54,-12.25
smd 1.5 x 1.7: M1 -1.36,13.9; M2 -1.36,-13.9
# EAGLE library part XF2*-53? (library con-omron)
OMRON FPC Connector 53 Pin Source: http://www.omron.com/ecb/products/pdf/fpc.pdf

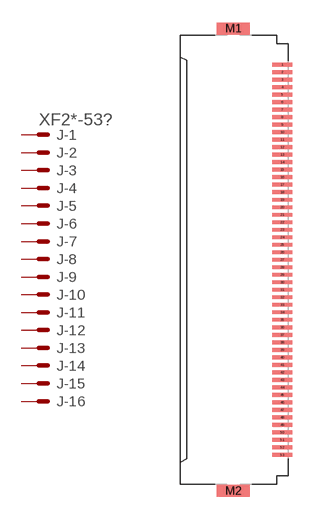
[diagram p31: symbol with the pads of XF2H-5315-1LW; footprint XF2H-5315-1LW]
Designator prefix J; gates -1=PV -2=P -3=P -4=P -5=P -6=P -7=P -8=P -9=P -10=P -11=P -12=P -13=P -14=P -15=P -16=P -17=P -18=P -19=P -20=P -21=P -22=P -23=P -24=P -25=P -26=P -27=P -28=P -29=P -30=P -31=P -32=P -33=P -34=P -35=P -36=P -37=P -38=P -39=P -40=P -41=P -42=P -43=P -44=P -45=P -46=P -47=P -48=P -49=P -50=P -51=P -52=P -53=P

## XF2H-5315-1LW (OC_FARNELL: unknown; OC_NEWARK: unknown)  [XF2H-5315-1LW]
1  -1:MSV  pas
2  -2:MS  pas
3  -3:MS  pas
4  -4:MS  pas
5  -5:MS  pas
6  -6:MS  pas
7  -7:MS  pas
8  -8:MS  pas
9  -9:MS  pas
10  -10:MS  pas
11  -11:MS  pas
12  -12:MS  pas
13  -13:MS  pas
14  -14:MS  pas
15  -15:MS  pas
16  -16:MS  pas
17  -17:MS  pas
18  -18:MS  pas
19  -19:MS  pas
20  -20:MS  pas
21  -21:MS  pas
22  -22:MS  pas
23  -23:MS  pas
24  -24:MS  pas
25  -25:MS  pas
26  -26:MS  pas
27  -27:MS  pas
28  -28:MS  pas
29  -29:MS  pas
30  -30:MS  pas
31  -31:MS  pas
32  -32:MS  pas
33  -33:MS  pas
34  -34:MS  pas
35  -35:MS  pas
36  -36:MS  pas
37  -37:MS  pas
38  -38:MS  pas
39  -39:MS  pas
40  -40:MS  pas
41  -41:MS  pas
42  -42:MS  pas
43  -43:MS  pas
44  -44:MS  pas
45  -45:MS  pas
46  -46:MS  pas
47  -47:MS  pas
48  -48:MS  pas
49  -49:MS  pas
50  -50:MS  pas
51  -51:MS  pas
52  -52:MS  pas
53  -53:MS  pas

## Footprint XF2H-5315-1LW (pad centres in mm)
Standard Rotary Backlock Type (0.5 mm-pitch) Source : http://www.omron.com/ecb/products/pdf/fpc.pdf
smd 1.3 x 0.25: 1 3.175,13; 2 3.175,12.5; 3 3.175,12; 4 3.175,11.5; 5 3.175,11; 6 3.175,10.5; 7 3.175,10; 8 3.175,9.5; 9 3.175,9; 10 3.175,8.5; 11 3.175,8; 12 3.175,7.5; 13 3.175,7; 14 3.175,6.5; 15 3.175,6; 16 3.175,5.5; 17 3.175,5; 18 3.175,4.5; 19 3.175,4; 20 3.175,3.5; 21 3.175,3; 22 3.175,2.5; 23 3.175,2; 24 3.175,1.5; 25 3.175,1; 26 3.175,0.5; 27 3.175,0; 28 3.175,-0.5; 29 3.175,-1; 30 3.175,-1.5; 31 3.175,-2; 32 3.175,-2.5; 33 3.175,-3; 34 3.175,-3.5; 35 3.175,-4; 36 3.175,-4.5; 37 3.175,-5; 38 3.175,-5.5; 39 3.175,-6; 40 3.175,-6.5; 41 3.175,-7; 42 3.175,-7.5; 43 3.175,-8; 44 3.175,-8.5; 45 3.175,-9; 46 3.175,-9.5; 47 3.175,-10; 48 3.175,-10.5; 49 3.175,-11; 50 3.175,-11.5; 51 3.175,-12; 52 3.175,-12.5; 53 3.175,-13
smd 2.2 x 0.8: M1 -0.075,15.4; M2 -0.075,-15.4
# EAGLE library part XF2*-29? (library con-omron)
OMRON FPC Connector Source : http://www.omron.com/ecb/products/pdf/fpc.pdf

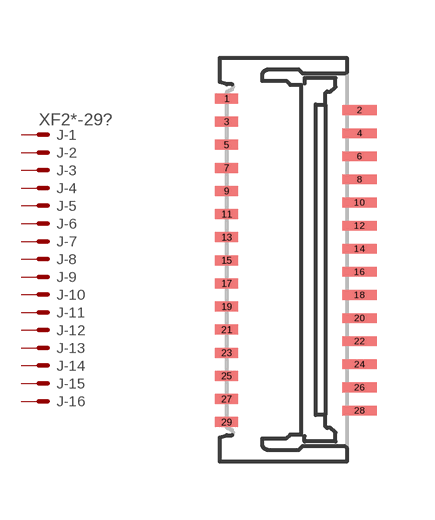
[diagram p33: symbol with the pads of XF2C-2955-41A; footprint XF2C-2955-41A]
Designator prefix J; gates -1=PV -2=P -3=P -4=P -5=P -6=P -7=P -8=P -9=P -10=P -11=P -12=P -13=P -14=P -15=P -16=P -17=P -18=P -19=P -20=P -21=P -22=P -23=P -24=P -25=P -26=P -27=P -28=P -29=P

## XF2-2955-41A (OC_FARNELL: unknown; OC_NEWARK: unknown)  [XF2C-2955-41A]
1  -1:MSV  pas
2  -2:MS  pas
3  -3:MS  pas
4  -4:MS  pas
5  -5:MS  pas
6  -6:MS  pas
7  -7:MS  pas
8  -8:MS  pas
9  -9:MS  pas
10  -10:MS  pas
11  -11:MS  pas
12  -12:MS  pas
13  -13:MS  pas
14  -14:MS  pas
15  -15:MS  pas
16  -16:MS  pas
17  -17:MS  pas
18  -18:MS  pas
19  -19:MS  pas
20  -20:MS  pas
21  -21:MS  pas
22  -22:MS  pas
23  -23:MS  pas
24  -24:MS  pas
25  -25:MS  pas
26  -26:MS  pas
27  -27:MS  pas
28  -28:MS  pas
29  -29:MS  pas

## Footprint XF2C-2955-41A (pad centres in mm)
Low-profile Rotary Backlock Type (0.3 mm-pitch) Source : http://www.omron.com/ecb/products/pdf/fpc.pdf
smd 0.6 x 0.26: 1 -1.8,4.2; 3 -1.8,3.6; 5 -1.8,3; 7 -1.8,2.4; 9 -1.8,1.8; 11 -1.8,1.2; 13 -1.8,0.6; 15 -1.8,0; 17 -1.8,-0.6; 19 -1.8,-1.2; 21 -1.8,-1.8; 23 -1.8,-2.4; 25 -1.8,-3; 27 -1.8,-3.6; 29 -1.8,-4.2
smd 0.9 x 0.25: 2 1.65,3.9; 4 1.65,3.3; 6 1.65,2.7; 8 1.65,2.1; 10 1.65,1.5; 12 1.65,0.9; 14 1.65,0.3; 16 1.65,-0.3; 18 1.65,-0.9; 20 1.65,-1.5; 22 1.65,-2.1; 24 1.65,-2.7; 26 1.65,-3.3; 28 1.65,-3.9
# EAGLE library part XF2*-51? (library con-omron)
OMRON FPC Connector Source : http://www.omron.com/ecb/products/pdf/fpc.pdf

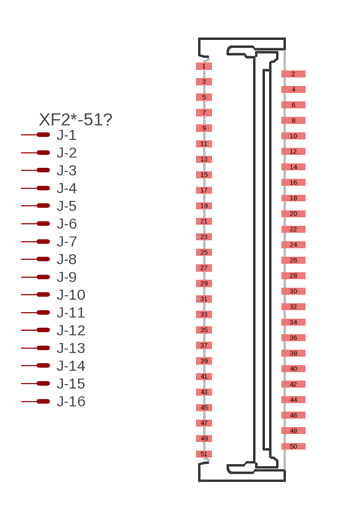
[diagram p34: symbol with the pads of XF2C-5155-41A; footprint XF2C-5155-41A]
Designator prefix J; gates -1=PV -2=P -3=P -4=P -5=P -6=P -7=P -8=P -9=P -10=P -11=P -12=P -13=P -14=P -15=P -16=P -17=P -18=P -19=P -20=P -21=P -22=P -23=P -24=P -25=P -26=P -27=P -28=P -29=P -30=P -31=P -32=P -33=P -34=P -35=P -36=P -37=P -38=P -39=P -40=P -41=P -42=P -43=P -44=P -45=P -46=P -47=P -48=P -49=P -50=P -51=P

## XF2-5155-41A (OC_FARNELL: unknown; OC_NEWARK: unknown)  [XF2C-5155-41A]
1  -1:MSV  pas
2  -2:MS  pas
3  -3:MS  pas
4  -4:MS  pas
5  -5:MS  pas
6  -6:MS  pas
7  -7:MS  pas
8  -8:MS  pas
9  -9:MS  pas
10  -10:MS  pas
11  -11:MS  pas
12  -12:MS  pas
13  -13:MS  pas
14  -14:MS  pas
15  -15:MS  pas
16  -16:MS  pas
17  -17:MS  pas
18  -18:MS  pas
19  -19:MS  pas
20  -20:MS  pas
21  -21:MS  pas
22  -22:MS  pas
23  -23:MS  pas
24  -24:MS  pas
25  -25:MS  pas
26  -26:MS  pas
27  -27:MS  pas
28  -28:MS  pas
29  -29:MS  pas
30  -30:MS  pas
31  -31:MS  pas
32  -32:MS  pas
33  -33:MS  pas
34  -34:MS  pas
35  -35:MS  pas
36  -36:MS  pas
37  -37:MS  pas
38  -38:MS  pas
39  -39:MS  pas
40  -40:MS  pas
41  -41:MS  pas
42  -42:MS  pas
43  -43:MS  pas
44  -44:MS  pas
45  -45:MS  pas
46  -46:MS  pas
47  -47:MS  pas
48  -48:MS  pas
49  -49:MS  pas
50  -50:MS  pas
51  -51:MS  pas

## Footprint XF2C-5155-41A (pad centres in mm)
Low-profile Rotary Backlock Type (0.3 mm-pitch) Source : http://www.omron.com/ecb/products/pdf/fpc.pdf
smd 0.6 x 0.26: 1 -1.8,7.5; 3 -1.8,6.9; 5 -1.8,6.3; 7 -1.8,5.7; 9 -1.8,5.1; 11 -1.8,4.5; 13 -1.8,3.9; 15 -1.8,3.3; 17 -1.8,2.7; 19 -1.8,2.1; 21 -1.8,1.5; 23 -1.8,0.9; 25 -1.8,0.3; 27 -1.8,-0.3; 29 -1.8,-0.9; 31 -1.8,-1.5; 33 -1.8,-2.1; 35 -1.8,-2.7; 37 -1.8,-3.3; 39 -1.8,-3.9; 41 -1.8,-4.5; 43 -1.8,-5.1; 45 -1.8,-5.7; 47 -1.8,-6.3; 49 -1.8,-6.9; 51 -1.8,-7.5
smd 0.9 x 0.25: 2 1.65,7.2; 4 1.65,6.6; 6 1.65,6; 8 1.65,5.4; 10 1.65,4.8; 12 1.65,4.2; 14 1.65,3.6; 16 1.65,3; 18 1.65,2.4; 20 1.65,1.8; 22 1.65,1.2; 24 1.65,0.6; 26 1.65,0; 28 1.65,-0.6; 30 1.65,-1.2; 32 1.65,-1.8; 34 1.65,-2.4; 36 1.65,-3; 38 1.65,-3.6; 40 1.65,-4.2; 42 1.65,-4.8; 44 1.65,-5.4; 46 1.65,-6; 48 1.65,-6.6; 50 1.65,-7.2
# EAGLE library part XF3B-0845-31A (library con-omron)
Rotary Backlock Connector (0.3-mm Pitch, Dual Contact) Source: Data sheet

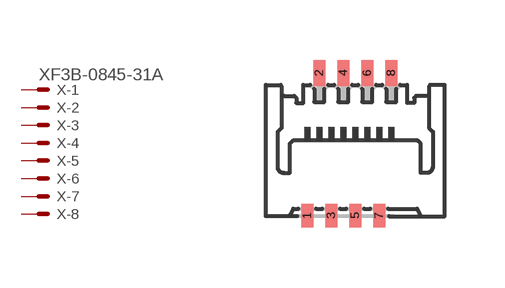
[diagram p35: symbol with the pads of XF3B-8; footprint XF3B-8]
Designator prefix X; gates -1=PV -2=P -3=P -4=P -5=P -6=P -7=P -8=P

## XF3B-0845-31A  [XF3B-8]
1  -1:MSV  pas
2  -2:MS  pas
3  -3:MS  pas
4  -4:MS  pas
5  -5:MS  pas
6  -6:MS  pas
7  -7:MS  pas
8  -8:MS  pas

## Footprint XF3B-8 (pad centres in mm)
Rotary Backlock Connector (0.3-mm Pitch, Dual Contact) Source: Data sheet
smd 0.3 x 0.6: 1 -1.2,-1.775; 3 -0.6,-1.775; 5 0,-1.775; 7 0.6,-1.775
smd 0.3 x 0.65: 2 -0.9,1.8; 4 -0.3,1.8; 6 0.3,1.8; 8 0.9,1.8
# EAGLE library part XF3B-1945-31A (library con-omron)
Rotary Backlock Connector (0.3-mm Pitch, Dual Contact) Source: Data sheet

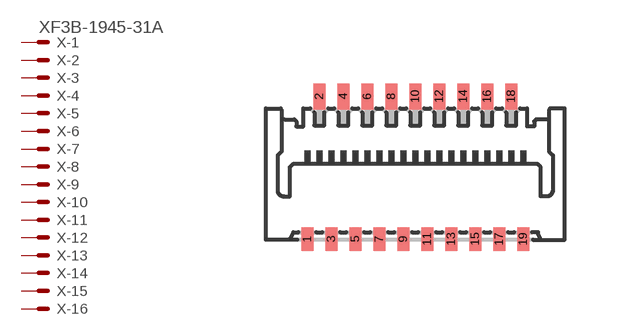
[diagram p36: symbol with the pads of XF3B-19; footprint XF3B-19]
Designator prefix X; gates -1=PV -2=P -3=P -4=P -5=P -6=P -7=P -8=P -9=P -10=P -11=P -12=P -13=P -14=P -15=P -16=P -17=P -18=P -19=P

## XF3B-1945-31A  [XF3B-19]
1  -1:MSV  pas
2  -2:MS  pas
3  -3:MS  pas
4  -4:MS  pas
5  -5:MS  pas
6  -6:MS  pas
7  -7:MS  pas
8  -8:MS  pas
9  -9:MS  pas
10  -10:MS  pas
11  -11:MS  pas
12  -12:MS  pas
13  -13:MS  pas
14  -14:MS  pas
15  -15:MS  pas
16  -16:MS  pas
17  -17:MS  pas
18  -18:MS  pas
19  -19:MS  pas

## Footprint XF3B-19 (pad centres in mm)
Rotary Backlock Connector (0.3-mm Pitch, Dual Contact) Source: Data sheet
smd 0.3 x 0.6: 1 -2.7,-1.775; 3 -2.1,-1.775; 5 -1.5,-1.775; 7 -0.9,-1.775; 9 -0.3,-1.775; 11 0.3,-1.775; 13 0.9,-1.775; 15 1.5,-1.775; 17 2.1,-1.775; 19 2.7,-1.775
smd 0.3 x 0.65: 2 -2.4,1.8; 4 -1.8,1.8; 6 -1.2,1.8; 8 -0.6,1.8; 10 0,1.8; 12 0.6,1.8; 14 1.2,1.8; 16 1.8,1.8; 18 2.4,1.8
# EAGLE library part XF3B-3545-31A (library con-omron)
Rotary Backlock Connector (0.3-mm Pitch, Dual Contact) Source: Data sheet

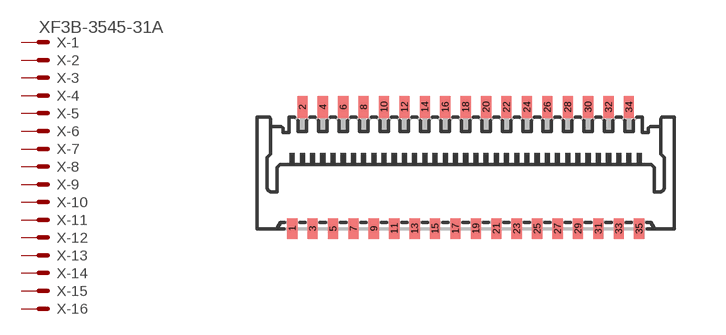
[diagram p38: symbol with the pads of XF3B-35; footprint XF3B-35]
Designator prefix X; gates -1=PV -2=P -3=P -4=P -5=P -6=P -7=P -8=P -9=P -10=P -11=P -12=P -13=P -14=P -15=P -16=P -17=P -18=P -19=P -20=P -21=P -22=P -23=P -24=P -25=P -26=P -27=P -28=P -29=P -30=P -31=P -32=P -33=P -34=P -35=P

## XF3B-3545-31A  [XF3B-35]
1  -1:MSV  pas
2  -2:MS  pas
3  -3:MS  pas
4  -4:MS  pas
5  -5:MS  pas
6  -6:MS  pas
7  -7:MS  pas
8  -8:MS  pas
9  -9:MS  pas
10  -10:MS  pas
11  -11:MS  pas
12  -12:MS  pas
13  -13:MS  pas
14  -14:MS  pas
15  -15:MS  pas
16  -16:MS  pas
17  -17:MS  pas
18  -18:MS  pas
19  -19:MS  pas
20  -20:MS  pas
21  -21:MS  pas
22  -22:MS  pas
23  -23:MS  pas
24  -24:MS  pas
25  -25:MS  pas
26  -26:MS  pas
27  -27:MS  pas
28  -28:MS  pas
29  -29:MS  pas
30  -30:MS  pas
31  -31:MS  pas
32  -32:MS  pas
33  -33:MS  pas
34  -34:MS  pas
35  -35:MS  pas

## Footprint XF3B-35 (pad centres in mm)
Rotary Backlock Connector (0.3-mm Pitch, Dual Contact) Source: Data sheet
smd 0.3 x 0.6: 1 -5.1,-1.775; 3 -4.5,-1.775; 5 -3.9,-1.775; 7 -3.3,-1.775; 9 -2.7,-1.775; 11 -2.1,-1.775; 13 -1.5,-1.775; 15 -0.9,-1.775; 17 -0.3,-1.775; 19 0.3,-1.775; 21 0.9,-1.775; 23 1.5,-1.775; 25 2.1,-1.775; 27 2.7,-1.775; 29 3.3,-1.775; 31 3.9,-1.775; 33 4.5,-1.775; 35 5.1,-1.775
smd 0.3 x 0.65: 2 -4.8,1.8; 4 -4.2,1.8; 6 -3.6,1.8; 8 -3,1.8; 10 -2.4,1.8; 12 -1.8,1.8; 14 -1.2,1.8; 16 -0.6,1.8; 18 0,1.8; 20 0.6,1.8; 22 1.2,1.8; 24 1.8,1.8; 26 2.4,1.8; 28 3,1.8; 30 3.6,1.8; 32 4.2,1.8; 34 4.8,1.8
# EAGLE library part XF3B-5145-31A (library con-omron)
Rotary Backlock Connector (0.3-mm Pitch, Dual Contact) Source: Data sheet

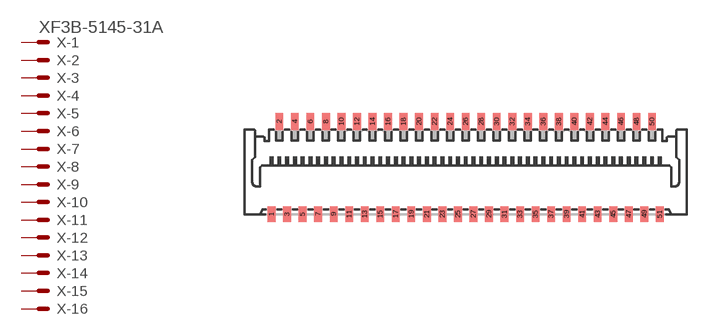
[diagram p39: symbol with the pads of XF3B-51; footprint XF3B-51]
Designator prefix X; gates -1=PV -2=P -3=P -4=P -5=P -6=P -7=P -8=P -9=P -10=P -11=P -12=P -13=P -14=P -15=P -16=P -17=P -18=P -19=P -20=P -21=P -22=P -23=P -24=P -25=P -26=P -27=P -28=P -29=P -30=P -31=P -32=P -33=P -34=P -35=P -36=P -37=P -38=P -39=P -40=P -41=P -42=P -43=P -44=P -45=P -46=P -47=P -48=P -49=P -50=P -51=P

## XF3B-5145-31A  [XF3B-51]
1  -1:MSV  pas
2  -2:MS  pas
3  -3:MS  pas
4  -4:MS  pas
5  -5:MS  pas
6  -6:MS  pas
7  -7:MS  pas
8  -8:MS  pas
9  -9:MS  pas
10  -10:MS  pas
11  -11:MS  pas
12  -12:MS  pas
13  -13:MS  pas
14  -14:MS  pas
15  -15:MS  pas
16  -16:MS  pas
17  -17:MS  pas
18  -18:MS  pas
19  -19:MS  pas
20  -20:MS  pas
21  -21:MS  pas
22  -22:MS  pas
23  -23:MS  pas
24  -24:MS  pas
25  -25:MS  pas
26  -26:MS  pas
27  -27:MS  pas
28  -28:MS  pas
29  -29:MS  pas
30  -30:MS  pas
31  -31:MS  pas
32  -32:MS  pas
33  -33:MS  pas
34  -34:MS  pas
35  -35:MS  pas
36  -36:MS  pas
37  -37:MS  pas
38  -38:MS  pas
39  -39:MS  pas
40  -40:MS  pas
41  -41:MS  pas
42  -42:MS  pas
43  -43:MS  pas
44  -44:MS  pas
45  -45:MS  pas
46  -46:MS  pas
47  -47:MS  pas
48  -48:MS  pas
49  -49:MS  pas
50  -50:MS  pas
51  -51:MS  pas

## Footprint XF3B-51 (pad centres in mm)
Rotary Backlock Connector (0.3-mm Pitch, Dual Contact) Source: Data sheet
smd 0.3 x 0.6: 1 -7.5,-1.775; 3 -6.9,-1.775; 5 -6.3,-1.775; 7 -5.7,-1.775; 9 -5.1,-1.775; 11 -4.5,-1.775; 13 -3.9,-1.775; 15 -3.3,-1.775; 17 -2.7,-1.775; 19 -2.1,-1.775; 21 -1.5,-1.775; 23 -0.9,-1.775; 25 -0.3,-1.775; 27 0.3,-1.775; 29 0.9,-1.775; 31 1.5,-1.775; 33 2.1,-1.775; 35 2.7,-1.775; 37 3.3,-1.775; 39 3.9,-1.775; 41 4.5,-1.775; 43 5.1,-1.775; 45 5.7,-1.775; 47 6.3,-1.775; 49 6.9,-1.775; 51 7.5,-1.775
smd 0.3 x 0.65: 2 -7.2,1.8; 4 -6.6,1.8; 6 -6,1.8; 8 -5.4,1.8; 10 -4.8,1.8; 12 -4.2,1.8; 14 -3.6,1.8; 16 -3,1.8; 18 -2.4,1.8; 20 -1.8,1.8; 22 -1.2,1.8; 24 -0.6,1.8; 26 0,1.8; 28 0.6,1.8; 30 1.2,1.8; 32 1.8,1.8; 34 2.4,1.8; 36 3,1.8; 38 3.6,1.8; 40 4.2,1.8; 42 4.8,1.8; 44 5.4,1.8; 46 6,1.8; 48 6.6,1.8; 50 7.2,1.8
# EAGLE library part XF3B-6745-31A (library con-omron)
Rotary Backlock Connector (0.3-mm Pitch, Dual Contact) Source: Data sheet

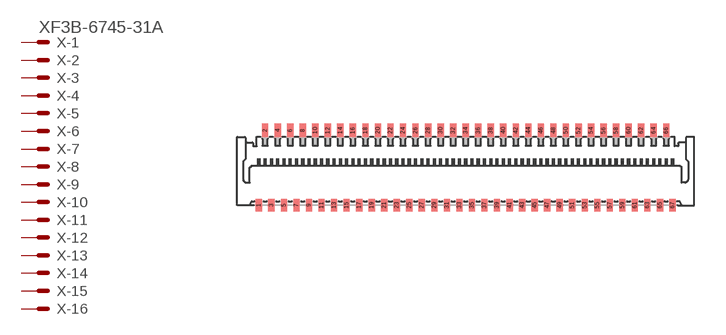
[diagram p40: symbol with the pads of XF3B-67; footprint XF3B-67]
Designator prefix X; gates -1=PV -2=P -3=P -4=P -5=P -6=P -7=P -8=P -9=P -10=P -11=P -12=P -13=P -14=P -15=P -16=P -17=P -18=P -19=P -20=P -21=P -22=P -23=P -24=P -25=P -26=P -27=P -28=P -29=P -30=P -31=P -32=P -33=P -34=P -35=P -36=P -37=P -38=P -39=P -40=P -41=P -42=P -43=P -44=P -45=P -46=P -47=P -48=P -49=P -50=P -51=P -52=P -53=P -54=P -55=P -56=P -57=P -58=P -59=P -60=P -61=P -62=P -63=P -64=P -65=P -66=P -67=P

## XF3B-6745-31A  [XF3B-67]
1  -1:MSV  pas
2  -2:MS  pas
3  -3:MS  pas
4  -4:MS  pas
5  -5:MS  pas
6  -6:MS  pas
7  -7:MS  pas
8  -8:MS  pas
9  -9:MS  pas
10  -10:MS  pas
11  -11:MS  pas
12  -12:MS  pas
13  -13:MS  pas
14  -14:MS  pas
15  -15:MS  pas
16  -16:MS  pas
17  -17:MS  pas
18  -18:MS  pas
19  -19:MS  pas
20  -20:MS  pas
21  -21:MS  pas
22  -22:MS  pas
23  -23:MS  pas
24  -24:MS  pas
25  -25:MS  pas
26  -26:MS  pas
27  -27:MS  pas
28  -28:MS  pas
29  -29:MS  pas
30  -30:MS  pas
31  -31:MS  pas
32  -32:MS  pas
33  -33:MS  pas
34  -34:MS  pas
35  -35:MS  pas
36  -36:MS  pas
37  -37:MS  pas
38  -38:MS  pas
39  -39:MS  pas
40  -40:MS  pas
41  -41:MS  pas
42  -42:MS  pas
43  -43:MS  pas
44  -44:MS  pas
45  -45:MS  pas
46  -46:MS  pas
47  -47:MS  pas
48  -48:MS  pas
49  -49:MS  pas
50  -50:MS  pas
51  -51:MS  pas
52  -52:MS  pas
53  -53:MS  pas
54  -54:MS  pas
55  -55:MS  pas
56  -56:MS  pas
57  -57:MS  pas
58  -58:MS  pas
59  -59:MS  pas
60  -60:MS  pas
61  -61:MS  pas
62  -62:MS  pas
63  -63:MS  pas
64  -64:MS  pas
65  -65:MS  pas
66  -66:MS  pas
67  -67:MS  pas

## Footprint XF3B-67 (pad centres in mm)
Rotary Backlock Connector (0.3-mm Pitch, Dual Contact) Source: Data sheet
smd 0.3 x 0.6: 1 -9.9,-1.775; 3 -9.3,-1.775; 5 -8.7,-1.775; 7 -8.1,-1.775; 9 -7.5,-1.775; 11 -6.9,-1.775; 13 -6.3,-1.775; 15 -5.7,-1.775; 17 -5.1,-1.775; 19 -4.5,-1.775; 21 -3.9,-1.775; 23 -3.3,-1.775; 25 -2.7,-1.775; 27 -2.1,-1.775; 29 -1.5,-1.775; 31 -0.9,-1.775; 33 -0.3,-1.775; 35 0.3,-1.775; 37 0.9,-1.775; 39 1.5,-1.775; 41 2.1,-1.775; 43 2.7,-1.775; 45 3.3,-1.775; 47 3.9,-1.775; 49 4.5,-1.775; 51 5.1,-1.775; 53 5.7,-1.775; 55 6.3,-1.775; 57 6.9,-1.775; 59 7.5,-1.775; 61 8.1,-1.775; 63 8.7,-1.775; 65 9.3,-1.775; 67 9.9,-1.775
smd 0.3 x 0.65: 2 -9.6,1.8; 4 -9,1.8; 6 -8.4,1.8; 8 -7.8,1.8; 10 -7.2,1.8; 12 -6.6,1.8; 14 -6,1.8; 16 -5.4,1.8; 18 -4.8,1.8; 20 -4.2,1.8; 22 -3.6,1.8; 24 -3,1.8; 26 -2.4,1.8; 28 -1.8,1.8; 30 -1.2,1.8; 32 -0.6,1.8; 34 0,1.8; 36 0.6,1.8; 38 1.2,1.8; 40 1.8,1.8; 42 2.4,1.8; 44 3,1.8; 46 3.6,1.8; 48 4.2,1.8; 50 4.8,1.8; 52 5.4,1.8; 54 6,1.8; 56 6.6,1.8; 58 7.2,1.8; 60 7.8,1.8; 62 8.4,1.8; 64 9,1.8; 66 9.6,1.8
